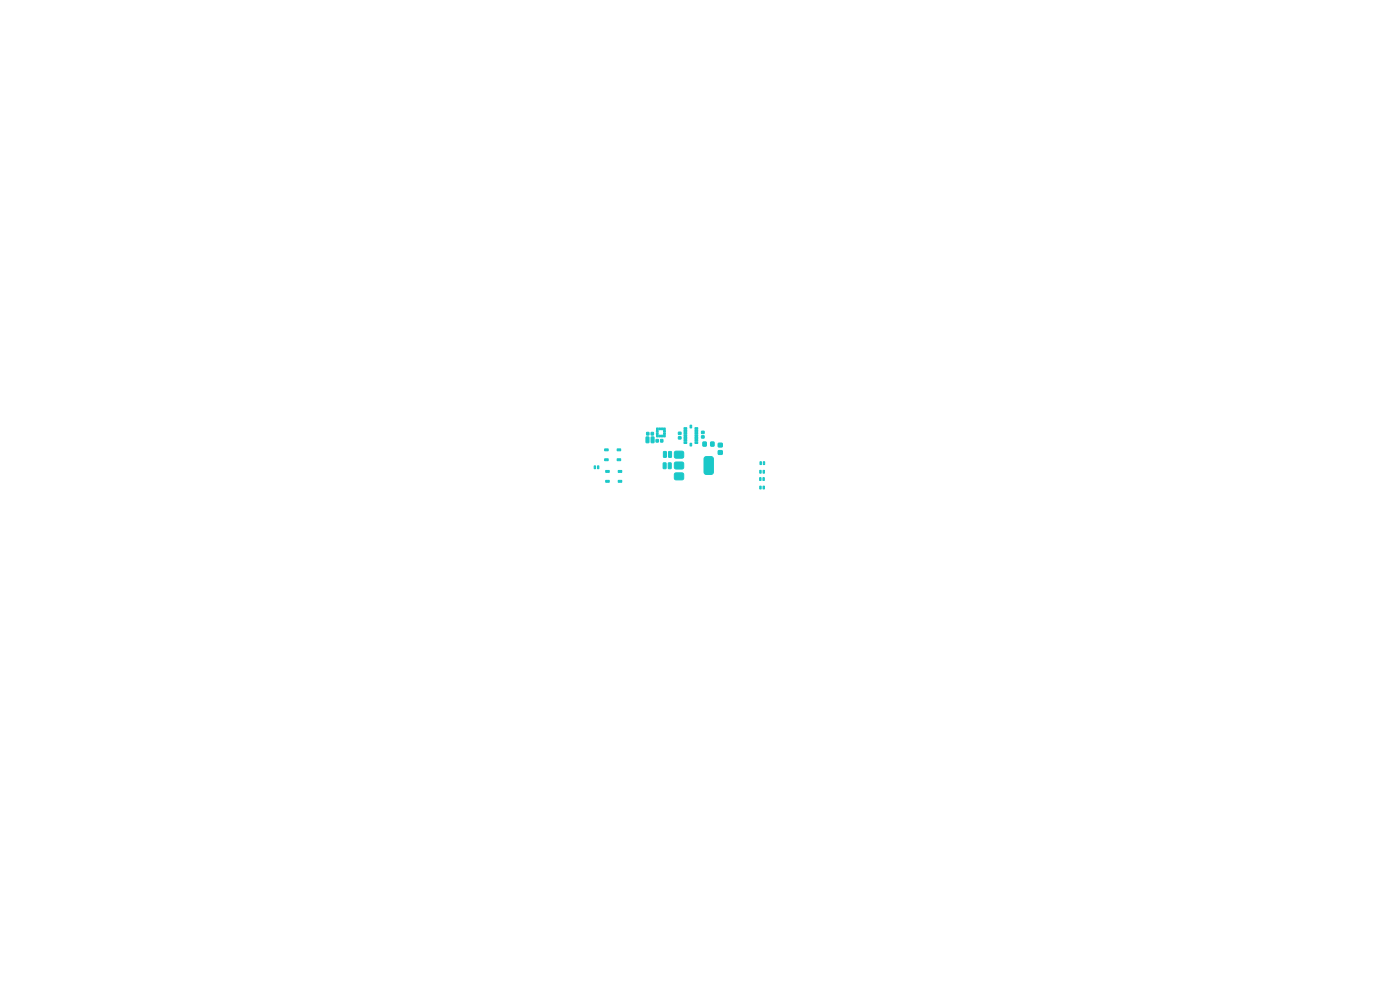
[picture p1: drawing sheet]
<svg xmlns="http://www.w3.org/2000/svg" width="297mm" height="210mm" viewBox="0 0 297 210" stroke-linecap="round" stroke-linejoin="round" font-family="sans-serif">
<g fill="#1ac8c8" stroke="#1ac8c8" stroke-width=".21">
<path d="M126.1 98.8h.3v.6h-.3z"/>
<path d="M126.8 98.8h.3v.6h-.3z"/>
<path d="M161.2 101.3h.3v.6h-.3z"/>
<path d="M161.9 101.3h.3v.6h-.3z"/>
<path d="M161.2 99.8h.3v.6h-.3z"/>
<path d="M161.9 99.8h.3v.6h-.3z"/>
<path d="M161.2 103.1h.3v.6h-.3z"/>
<path d="M161.9 103.1h.3v.6h-.3z"/>
<path d="M161.2 98h.3v.5h-.3z"/>
<path d="M161.9 98h.3v.5h-.3z"/>
<path d="M148.8 92.4h.6v.5h-.6z"/>
<path d="M148.8 91.5h.6v.5h-.6z"/>
<path d="M138.1 91.7h.5v.6h-.5z"/>
<path d="M137.2 91.7h.5v.6h-.5z"/>
<path d="M128.5 99.8h.7v.4h-.7z"/>
<path d="M131.2 99.8h.7v.4h-.7z"/>
<path d="M150.8 93.8h.7v.8h-.7z"/>
<path d="M149.1 93.8h.7v.8h-.7z"/>
<path d="M141.8 98.2l.6 .1-.1 1.1-.5-.1z"/>
<path d="M140.7 98.2l.6 .1-.1 1.1-.5-.1z"/>
<path d="M128.3 97.3h.7v.4h-.7z"/>
<path d="M130.9 97.3h.8v.4h-.8z"/>
<path d="M138.2 92.7l.6 .1-.1 1.1-.6-.1z"/>
<path d="M137.1 92.7l.6 .1-.1 1.1-.6-.1z"/>
<path d="M143.1 100.5l.3-.2 1.5 .1 .2 .3-.1 .9-.3 .2-1.5-.1-.2-.3z"/>
<path d="M143.1 98.2l.3-.2 1.5 .1 .2 .3-.1 .9-.3 .2-1.5-.1-.2-.3z"/>
<path d="M149.5 97l.2-.1 1.2-.1 .4 .3v3l-.2 .5h-1.4l-.3-.2-.1-3z"/>
<path d="M143.2 95.8h1.7l.2 .3-.1 .9-.3 .2-1.5-.1-.2-.3 .1-.8z"/>
<path d="M140.8 92.3h.3v.4h-.3z"/>
<path d="M140.3 92.3h.3v.4h-.3z"/>
<path d="M139.8 92.3h.3v.4h-.3z"/>
<path d="M139.3 92.3h.3v.4h-.3z"/>
<path d="M139.2 91.8h.4v.4h-.4z"/>
<path d="M139.2 91.3h.4v.4h-.4z"/>
<path d="M139.3 90.8h.3v.4h-.3z"/>
<path d="M139.8 90.8h.3v.4h-.3z"/>
<path d="M140.3 90.8h.3v.4h-.3z"/>
<path d="M140.8 90.8h.3v.4h-.3z"/>
<path d="M140.8 91.3h.4v.4h-.4z"/>
<path d="M140.8 91.8h.4v.4h-.4z"/>
<path d="M152.4 95.6h.8v.8h-.8z"/>
<path d="M152.4 94h.8v.8h-.8z"/>
<path d="M143.9 91.7h.6v.5h-.6z"/>
<path d="M143.9 92.6h.6v.5h-.6z"/>
<path d="M139.2 93.2h.5v.6h-.5z"/>
<path d="M140.1 93.2h.5v.6h-.5z"/>
<path d="M128.5 101.9h.7v.4h-.7z"/>
<path d="M131.2 101.9h.7v.4h-.7z"/>
<path d="M128.3 95.2h.7v.4h-.7z"/>
<path d="M130.9 95.2h.8v.4h-.8z"/>
<path d="M141.9 95.8l.6 .1-.1 1.1-.6-.1z"/>
<path d="M140.8 95.8l.6 .1-.1 1.1-.6-.1z"/>
<path d="M145.1 90.7h.6v.4h-.6z"/>
<path d="M145.1 91.2h.6v.4h-.6z"/>
<path d="M145.1 91.7h.6v.4h-.6z"/>
<path d="M145.1 92.2h.6v.4h-.6z"/>
<path d="M145.1 92.7h.6v.4h-.6z"/>
<path d="M145.1 93.2h.6v.4h-.6z"/>
<path d="M145.1 93.7h.6v.4h-.6z"/>
<path d="M146.4 94h.3v.6h-.3z"/>
<path d="M147.4 93.7h.6v.4h-.6z"/>
<path d="M147.4 93.2h.6v.4h-.6z"/>
<path d="M147.4 92.7h.6v.4h-.6z"/>
<path d="M147.4 92.2h.6v.4h-.6z"/>
<path d="M147.4 91.7h.6v.4h-.6z"/>
<path d="M147.4 91.2h.6v.4h-.6z"/>
<path d="M147.4 90.7h.6v.4h-.6z"/>
<path d="M146.4 90.2h.3v.6h-.3z"/>
</g>
</svg>
